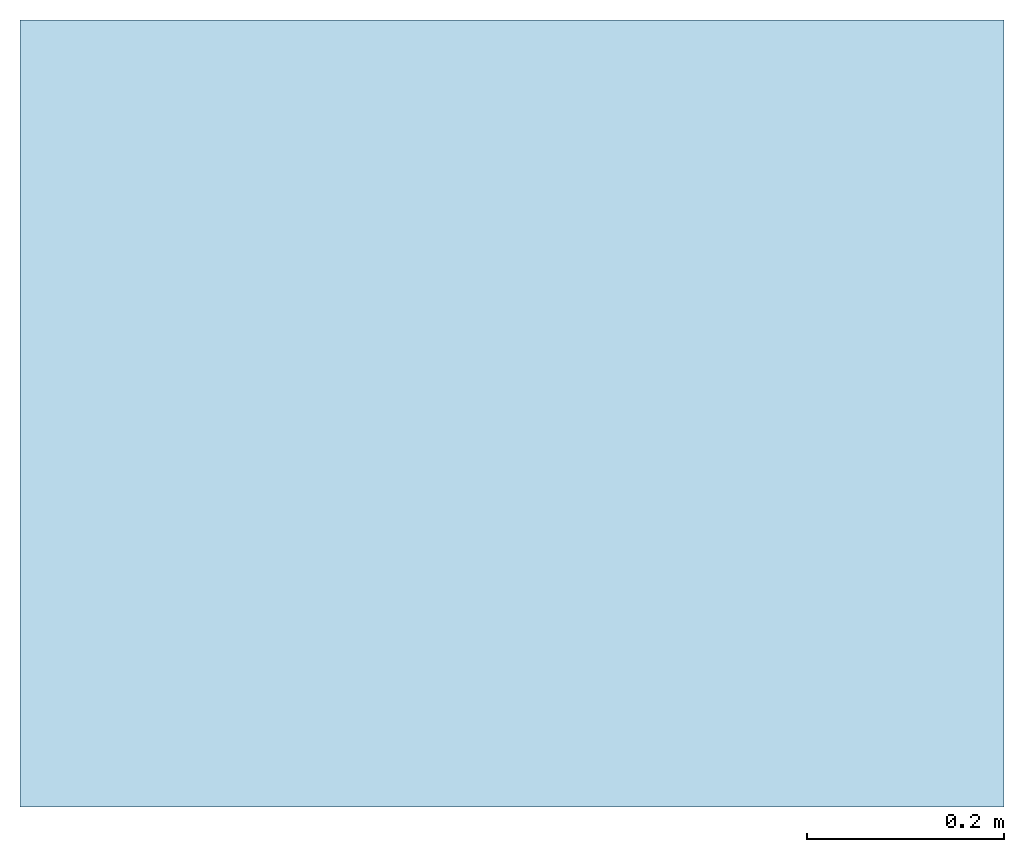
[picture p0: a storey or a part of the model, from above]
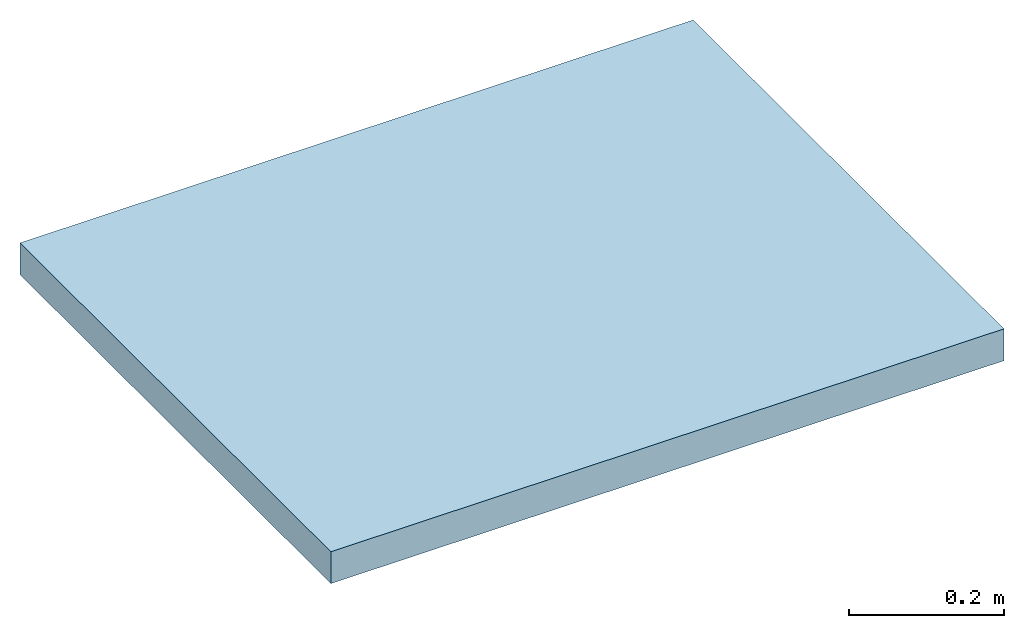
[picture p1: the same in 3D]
Properties of the parts of a building model (IFC2X3)

# File
Description: ViewDefinition [CoordinationView]
File name: Номер проекта
Time: 2018-08-31T10:18:41
Written by: The EXPRESS Data Manager Version 5.02.0100.07 : 28 Aug 2013
Made in: 20150714_1515(x64) - Exporter 16.0.490.0 - Default UI
Comment: STEP Physical File produced by: The EXPRESS Data Manager Version 5.02.0100.07 : 28 Aug 2013 * Module: EDMstepFileFactory/EDMstandAlone * Creation date: Fri Aug 31 10:18:41 2018 * Host: 43-120 * Database: C:\Users\I247A~1.VOI\AppData\Local\Temp\{5D66C3AF-6563-482F-86B7-4452C558BDF8}\ifc * Database version: 5507 * Database creation date: Fri Aug 31 10:18:41 2018 * Schema: IFC2X3 * Model: DataRepository.ifc * Model creation date: Fri Aug 31 10:18:41 2018 * Header model: DataRepository.ifc_HeaderModel * Header model creation date: Fri Aug 31 10:18:41 2018 * EDMuser: sdai-user * EDMgroup: sdai-group * License ID and type: 5605 : Permanent license. Expiry date: * EDMstepFileFactory options: 020000

# IfcProject, Номер проекта
LongName: Наименование проекта; Phase: Статус проекта

# IfcSite, Default
RefLatitude: 55, 45, 25, 90026; RefLongitude: 37, 36, 54, 74707; RefElevation: 0 mm
Идентификация - Вариант конструкции: Главная модель
Прочее - Адрес проекта: Укажите адрес; Дата утверждения проекта: Дата выпуска; Заказчик: Владелец; Категория: Сведения о проекте; Наименование проекта: Наименование проекта; Номер проекта: Номер проекта; Статус проекта: Статус проекта

# IfcBuilding
Pset_BuildingCommon - NumberOfStoreys: 1
Идентификация - Вариант конструкции: Главная модель
Прочее - Категория: Сведения о проекте; Адрес проекта: Укажите адрес; Дата утверждения проекта: Дата выпуска; Заказчик: Владелец; Наименование проекта: Наименование проекта; Номер проекта: Номер проекта; Статус проекта: Статус проекта

# IfcBuildingStorey, Уровень 1
LongName: Уровень 1; Elevation: 0 mm
Прочее - Категория: Уровни; Имя семейства: Уровень; Код типа: Уровень: Верхний брус 8 мм; Семейство: Уровень: Верхний брус 8 мм; Семейство и типоразмер: Уровень: Верхний брус 8 мм; Тип: Уровень: Верхний брус 8 мм
Зависимости - Фасад: 0 mm; Базовая отметка: Базовая точка проекта
Идентификация - Несущие конструкции: no; Имя: Уровень 1; Построение этажа: yes; Имя типа: Верхний брус 8 мм
Размеры - Расчетная высота: 0 mm
Графика - Вес линий: 1; Обозначение: Заголовок уровня - Окружность: Заголовок уровня - Окружность; Образец линий: Центр; Стандартное обозначение второго конца: yes; Стандартное обозначение первого конца: no; Цвет: 0

# IfcSlab: Перекрытие:ROLS_ISOMARKET_Плита ENERGOFLOOR 50/1-0,8 DEO-dm, Перекрытие:ROLS_ISOMARKET_Плита ENERGOFLOOR 50/1-0,8 DEO-dm:259215
In: Уровень 1
PredefinedType: FLOOR; Classification: ﻿﻿ ​ ​ ﻿ ﻿ ﻿ ​ ﻿ ​ ​ ﻿​ ﻿ ﻿ ﻿​ ﻿ ﻿ ​ ﻿ ﻿﻿ (Uniformat); Material: ROLS_ISOMARKET_Плита ENERGOFLOOR 50/1-0,8 DEO-dm 50 mm
Pset_SlabCommon - Reference: ROLS_ISOMARKET_Плита ENERGOFLOOR 50/1-0,8 DEO-dm; IsExternal: no; LoadBearing: yes; PitchAngle: 0 deg
Pset_ManufacturerTypeInformation - Manufacturer: ROLS ISOMARKET
Зависимости - Граница помещения: yes; Связь с формообразующим элементом: no; Смещение от уровня: 0 mm; Уровень: Уровень: Уровень 1
Идентификация - Вариант конструкции: Главная модель; Комментарии: ﻿﻿ ​ ​ ﻿ ﻿ ﻿ ​ ﻿ ​ ​ ﻿​ ﻿ ﻿ ﻿​ ﻿ ﻿ ​ ﻿ ﻿﻿; Разработано: support@bimlib.ru; BIM library: https://bimlib.ru/manufacturer/rols-isomarket/1769/; URL: http://www.rols-isomarket.ru/catalog/energofloor/plity-energofloor/; Изготовитель: ROLS ISOMARKET; Имя типа: ROLS_ISOMARKET_Плита ENERGOFLOOR 50/1-0,8 DEO-dm; Ключевая пометка: ﻿﻿ ​ ​ ﻿ ﻿ ﻿ ​ ﻿ ​ ​ ﻿​ ﻿ ﻿ ﻿​ ﻿ ﻿ ​ ﻿ ﻿﻿; Код по классификатору: ﻿﻿ ​ ​ ﻿ ﻿ ﻿ ​ ﻿ ​ ​ ﻿​ ﻿ ﻿ ﻿​ ﻿ ﻿ ​ ﻿ ﻿﻿; Комментарии к типоразмеру: EFRP5010/8; Описание: Плиты Energofloor – влагостойкий материал из пенополистирола, разработанный специально для создания дополнительного нижнего слоя в теплоизоляционных системах теплых полов.
Несущие конструкции - Включить аналитическую модель: no; Несущие конструкции: no
Прочее - Категория: Перекрытия; Код типа: Перекрытие: ROLS_ISOMARKET_Плита ENERGOFLOOR 50/1-0,8 DEO-dm; Семейство: Перекрытие: ROLS_ISOMARKET_Плита ENERGOFLOOR 50/1-0,8 DEO-dm; Семейство и типоразмер: Перекрытие: ROLS_ISOMARKET_Плита ENERGOFLOOR 50/1-0,8 DEO-dm; Тип: Перекрытие: ROLS_ISOMARKET_Плита ENERGOFLOOR 50/1-0,8 DEO-dm; Имя семейства: Перекрытие
Размеры - Объем: 0.04 m3; Отметка верха: 0 mm; Отметка низа: -50 mm; Периметр: 3600 mm; Площадь: 0.8 m2; Толщина: 50 mm
Стадии - Стадия возведения: Новая конструкция
Графика - Цвет штриховки при низкой детализации: 0
Свойства аналитической модели - Коэффициент поглощения: 0.7; Шероховатость: 3
Строительство - Толщина: 50 mm; Функция: Внутренние слои
